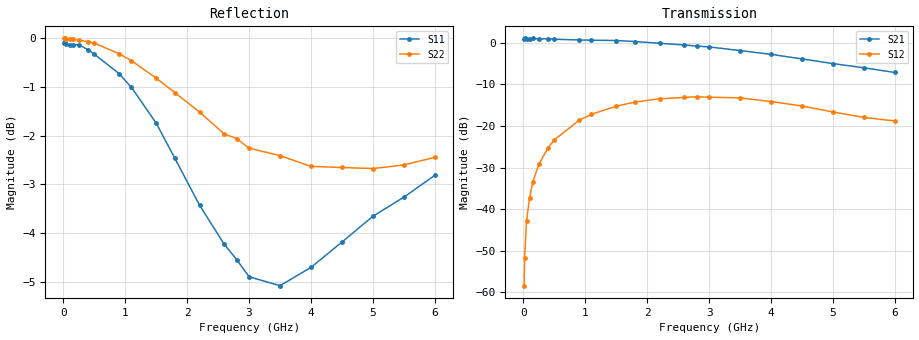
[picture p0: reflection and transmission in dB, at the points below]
! SIEMENS Small Signal Semiconductors
! BFP181
! Si NPN RF Bipolar Junction Transistor in SOT143
! VCE = 5 V  IC = 0.3 mA
! Common Emitter S-Parameters:  March  1996
# GHz  S  MA  R  50
!  f  S11  S21  S12  S22
! GHz  MAG  ANG  MAG  ANG  MAG  ANG  MAG  ANG
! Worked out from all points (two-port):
!   36 points, 10 MHz to 6 GHz, reference 50 ohm
!   highest |S21| = 1.05 dB at 20 MHz (marker M1); lowest = -7.2 dB at 6 GHz (marker M2)
!   |S21| within 3 dB of the highest: start of sweep to 3.54 GHz
!   lowest |S11| = -5.1 dB at 3.5 GHz (marker M3), VSWR 3.52, Z = 14.3 + j3.98 ohm
!   |S11| at or under -10 dB: nowhere
!   |S22| runs from -2.7 to 0.0 dB; largest |S21 - S12| = 1.1
!   S11 on the Smith chart (normalised r, x): 10 MHz: open; 900 MHz: 0.32, -2.54; 1.8 GHz: 0.28, -0.99; 2.8 GHz: 0.28, -0.27; 4 GHz: 0.29, +0.29; 6 GHz: 0.32, +0.96
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0.01  0.9879 -0.6  1.105 179.9  0.0012 85.0  0.9994 -0.1
0.02  0.9939 -0.8  1.129 179.6  0.0026 88.0  0.9995 -0.4
0.05  0.987 -2.1  1.123 177.5  0.0072 89.4  0.9976 -1.2
0.1  0.9845 -4.7  1.102 175.1  0.0137 85.7  0.9984 -2.4
0.15  0.9846 -7.0  1.125 172.7  0.021 84.5  0.9974 -3.5
0.25  0.9848 -11.8  1.109 167.7  0.0346 81.3  0.9951 -5.9
0.4  0.9728 -18.6  1.117 160.0  0.0549 76.1  0.9918 -9.5
0.5  0.9629 -23.9  1.102 154.9  0.068 72.5  0.9884 -11.7
0.9  0.9197 -42.4  1.081 136.2  0.1169 58.4  0.964 -20.8
1.1  0.8902 -52.4  1.073 127.0  0.138 51.8  0.9484 -25.1
1.5  0.8182 -72.9  1.064 109.4  0.1727 39.1  0.9098 -33.4
1.8  0.7533 -88.4  1.034 95.8  0.1934 30.5  0.8795 -39.0
2.2  0.6742 -111.0  0.986 78.8  0.2121 19.1  0.8399 -46.3
2.6  0.6145 -135.4  0.94 63.6  0.22 8.9  0.7975 -52.9
2.8  0.593 -147.7  0.913 55.4  0.2242 3.7  0.7891 -56.2
3  0.5694 -160.3  0.891 48.0  0.222 -1.4  0.7713 -59.6
3.5  0.5575 170.1  0.806 30.3  0.217 -12.1  0.7578 -67.7
4  0.5821 145.0  0.726 15.3  0.1964 -21.2  0.7388 -77.2
4.5  0.6179 125.3  0.639 2.1  0.1737 -28.6  0.7369 -87.6
5  0.6567 110.6  0.562 -8.6  0.1471 -31.8  0.735 -98.3
5.5  0.687 98.9  0.5 -17.7  0.1266 -29.4  0.7413 -109.2
6  0.7234 89.6  0.439 -25.4  0.1148 -24.6  0.7548 -120.4
